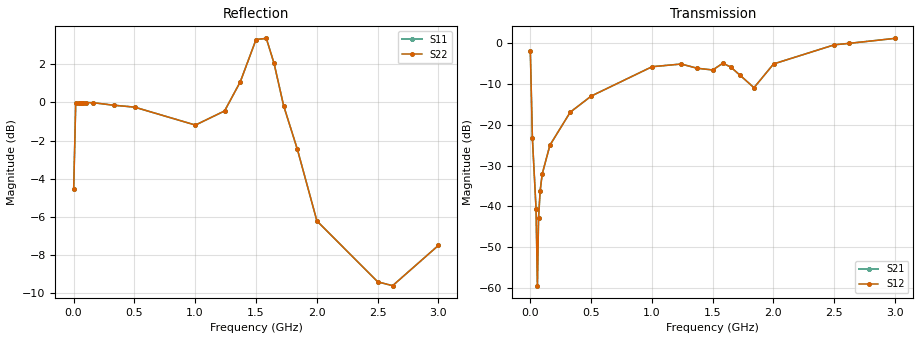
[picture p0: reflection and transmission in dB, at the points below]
!s-Parameter Generated by FASTRON Sdn. Bhd.
!FASTRON P/N : MICC-120X
!Keysight Technologies,E4991B,MY54100416,A.01.15
!Date: Fri Aug 28 11:10:13 2026
!Version  : Rev00 Fri Aug 28 11:10:13 2026
!Data & Calibration Information:
!PortZ  Port1:50+j0  Port2:50+j0
!When reading, reference impedance value at option line is always used.
! Remarks : This data is being provided solely for informational purposes.
!Freq	S11	S21	S12	S22
# Hz S dB R 50
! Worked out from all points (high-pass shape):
!   1601 points, 1 MHz to 3 GHz, reference 50 ohm
!   highest |S21| = 1.13 dB at 3 GHz (marker M1); lowest = -59.4 dB at 59.11 MHz (marker M2)
!   |S21| within 3 dB of the highest: 2.271 GHz to end of sweep
!   lowest |S11| = -9.6 dB at 2.623 GHz (marker M3), VSWR 1.99, Z = 45.5 - j33.2 ohm
!   |S11| at or under -10 dB: nowhere
!   |S22| runs from -9.6 to 3.6 dB; largest |S21 - S12| = 0
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1000000  -4.55 52.0  -2.06 -36.3  -2.06 -36.3  -4.55 52.0
1.786938e7  -0.03 3.9  -23.33 -85.0  -23.33 -85.0  -0.03 3.9
4.785938e7  -0.01 0.5  -40.59 -84.2  -40.59 -84.2  -0.01 0.5
5.910562e7  -0.01 -0.0  -59.42 24.8  -59.42 24.8  -0.01 -0.0
6.84775e7  -0.01 -0.4  -42.82 81.5  -42.82 81.5  -0.01 -0.4
8.159812e7  -0.01 -0.9  -36.21 85.2  -36.21 85.2  -0.01 -0.9
9.84675e7  -0.01 -1.4  -32.07 86.2  -32.07 86.2  -0.01 -1.4
1.621962e8  -0.02 -3.2  -25.00 85.5  -25.00 85.5  -0.02 -3.2
3.290156e8  -0.15 -8.2  -16.94 79.0  -16.94 79.0  -0.15 -8.2
5.014581e8  -0.25 -12.9  -13.00 76.2  -13.00 76.2  -0.25 -12.9
1.001916e9  -1.19 -30.8  -5.81 60.6  -5.81 60.6  -1.19 -30.8
1.241836e9  -0.45 -32.8  -5.15 68.6  -5.15 68.6  -0.45 -32.8
1.371168e9  1.08 -25.6  -6.18 92.5  -6.18 92.5  1.08 -25.6
1.5005e9  3.29 -3.5  -6.61 169.1  -6.61 169.1  3.29 -3.5
1.584847e9  3.35 14.9  -4.94 -138.1  -4.94 -138.1  3.35 14.9
1.648576e9  2.04 22.2  -5.90 -109.7  -5.90 -109.7  2.04 22.2
1.727299e9  -0.18 23.3  -7.95 -75.5  -7.95 -75.5  -0.18 23.3
1.839762e9  -2.45 9.3  -10.95 -25.4  -10.95 -25.4  -2.45 9.3
2.000958e9  -6.21 -17.6  -5.13 15.5  -5.13 15.5  -6.21 -17.6
2.501416e9  -9.40 -71.8  -0.44 19.8  -0.44 19.8  -9.40 -71.8
2.623251e9  -9.60 -78.6  -0.09 19.2  -0.09 19.2  -9.60 -78.6
3e9  -7.49 -98.0  1.13 21.5  1.13 21.5  -7.49 -98.0
